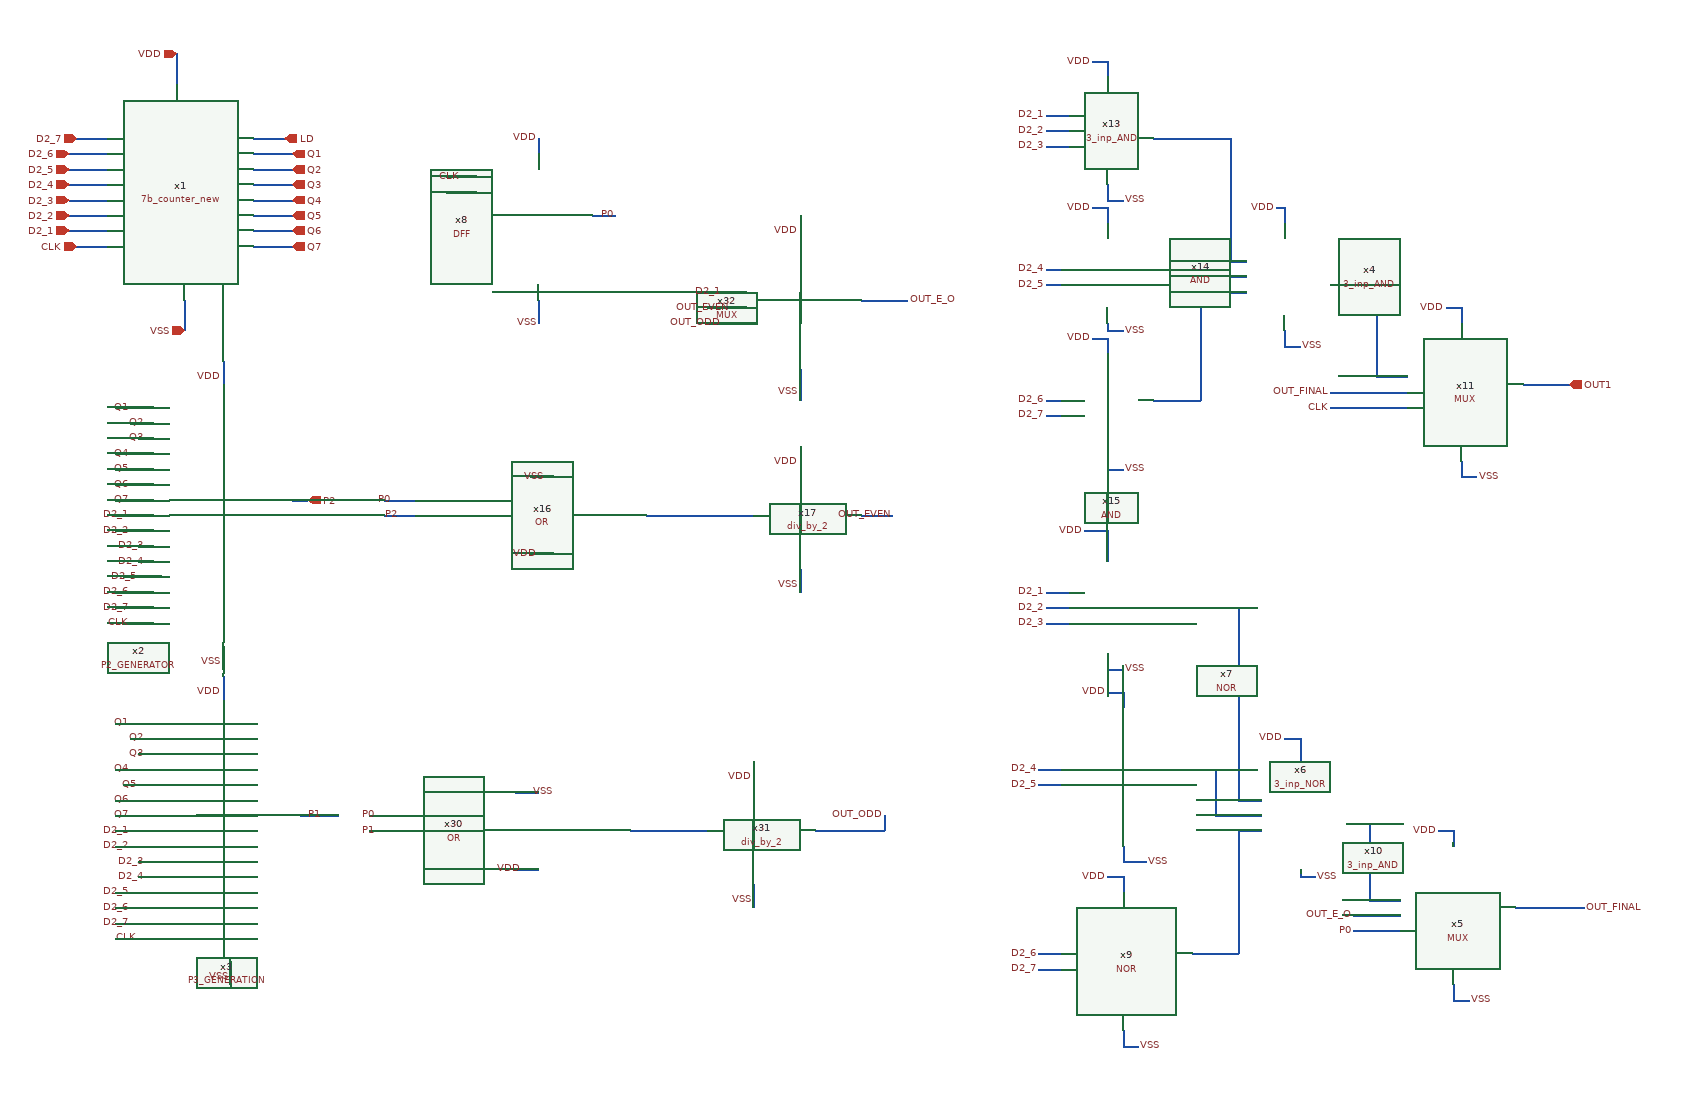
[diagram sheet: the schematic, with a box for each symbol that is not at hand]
v {xschem version=3.4.5 file_version=1.2
}
G {}
K {}
V {}
S {}
E {}
N 1970 -1710 1970 -1670 {
lab=VDD}
N 1980 -1390 1980 -1350 {
lab=VSS}
N 1840 -1460 1880 -1460 {
lab=CLK}
N 2070 -1600 2110 -1600 {
lab=LD}
N 1830 -1480 1880 -1480 {
lab=D2_1}
N 1830 -1520 1880 -1520 {
lab=D2_3}
N 1830 -1500 1880 -1500 {
lab=D2_2}
N 1830 -1540 1880 -1540 {
lab=D2_4}
N 1830 -1560 1880 -1560 {
lab=D2_5}
N 1830 -1580 1880 -1580 {
lab=D2_6}
N 1840 -1600 1880 -1600 {
lab=D2_7}
N 2070 -1580 2120 -1580 {
lab=Q1}
N 2070 -1560 2120 -1560 {
lab=Q2}
N 2070 -1540 2120 -1540 {
lab=Q3}
N 2070 -1520 2120 -1520 {
lab=Q4}
N 2070 -1500 2120 -1500 {
lab=Q5}
N 2070 -1480 2120 -1480 {
lab=Q6}
N 2070 -1460 2120 -1460 {
lab=Q7}
N 1890 -1250 1940 -1250 {
lab=Q1}
N 1890 -1090 1940 -1090 {
lab=D2_2}
N 1910 -1230 1940 -1230 {
lab=Q2}
N 1920 -1070 1940 -1070 {
lab=D2_3}
N 1920 -1210 1940 -1210 {
lab=Q3}
N 1920 -1050 1940 -1050 {
lab=D2_4}
N 1890 -1190 1940 -1190 {
lab=Q4}
N 1900 -1030 1950 -1030 {
lab=D2_5}
N 1890 -1170 1940 -1170 {
lab=Q5}
N 1890 -1010 1940 -1010 {
lab=D2_6}
N 1890 -1150 1940 -1150 {
lab=Q6}
N 1890 -990 1940 -990 {
lab=D2_7}
N 1890 -1130 1940 -1130 {
lab=Q7}
N 1890 -1110 1940 -1110 {
lab=D2_1}
N 2240 -1130 2280 -1130 {
lab=P0}
N 2240 -1110 2280 -1110 {
lab=P2}
N 2430 -1060 2460 -1060 {
lab=VDD}
N 2430 -1160 2460 -1160 {
lab=VSS}
N 2670 -1110 2720 -1110 {
lab=#net1}
N 2780 -1200 2780 -1170 {
lab=VDD}
N 2780 -1040 2780 -1010 {
lab=VSS}
N 2860 -1110 2900 -1110 {
lab=OUT_EVEN}
N 2320 -1550 2360 -1550 {
lab=CLK}
N 2320 -1530 2360 -1530 {
lab=LD}
N 1890 -840 1940 -840 {
lab=Q1}
N 1890 -680 1940 -680 {
lab=D2_2}
N 1910 -820 1940 -820 {
lab=Q2}
N 1920 -660 1940 -660 {
lab=D2_3}
N 1920 -800 1940 -800 {
lab=Q3}
N 1920 -640 1940 -640 {
lab=D2_4}
N 1890 -780 1940 -780 {
lab=Q4}
N 1890 -620 1940 -620 {
lab=D2_5}
N 1900 -760 1950 -760 {
lab=Q5}
N 1890 -600 1940 -600 {
lab=D2_6}
N 1890 -740 1940 -740 {
lab=Q6}
N 1890 -560 1940 -560 {
lab=CLK}
N 1890 -720 1940 -720 {
lab=Q7}
N 1890 -700 1940 -700 {
lab=D2_1}
N 2220 -720 2260 -720 {
lab=P0}
N 2220 -700 2260 -700 {
lab=P1}
N 2410 -650 2440 -650 {
lab=VDD}
N 2720 -630 2720 -600 {
lab=VSS}
N 2800 -700 2850 -700 {
lab=OUT_ODD}
N 2720 -790 2720 -760 {
lab=VDD}
N 2410 -750 2440 -750 {
lab=VSS}
N 2560 -700 2600 -700 {
lab=#net2}
N 2780 -1500 2780 -1460 {
lab=VDD}
N 2780 -1300 2780 -1260 {
lab=VSS}
N 2660 -1400 2710 -1400 {
lab=D2_1}
N 2660 -1380 2710 -1380 {
lab=OUT_EVEN}
N 2660 -1360 2710 -1360 {
lab=OUT_ODD}
N 2860 -1390 2920 -1390 {
lab=OUT_E_O}
N 2600 -700 2660 -700 {
lab=#net2}
N 2580 -1110 2670 -1110 {
lab=#net1}
N 2510 -1500 2540 -1500 {
lab=P0}
N 2440 -1390 2440 -1360 {
lab=VSS}
N 2440 -1600 2440 -1580 {
lab=VDD}
N 1900 -970 1940 -970 {
lab=CLK}
N 2120 -1130 2140 -1130 {
lab=P2}
N 1890 -580 1940 -580 {
lab=D2_7}
N 2130 -720 2180 -720 {
lab=P1}
N 2030 -1310 2030 -1280 {
lab=VDD}
N 2030 -900 2030 -870 {
lab=VDD}
N 2030 -940 2030 -910 {
lab=VSS}
N 2040 -530 2040 -500 {
lab=VSS}
N 2890 -720 2890 -700 {
lab=OUT_ODD}
N 2850 -700 2890 -700 {
lab=OUT_ODD}
N 3180 -1090 3180 -1050 {
lab=VDD}
N 3150 -1090 3180 -1090 {
lab=VDD}
N 3180 -930 3180 -910 {
lab=VSS}
N 3180 -910 3200 -910 {
lab=VSS}
N 3200 -880 3200 -860 {
lab=VDD}
N 3180 -880 3200 -880 {
lab=VDD}
N 3200 -680 3200 -660 {
lab=VSS}
N 3200 -660 3230 -660 {
lab=VSS}
N 3200 -640 3200 -620 {
lab=VDD}
N 3180 -640 3200 -640 {
lab=VDD}
N 3200 -440 3200 -420 {
lab=VSS}
N 3200 -420 3220 -420 {
lab=VSS}
N 3290 -540 3350 -540 {
lab=#net3}
N 3350 -700 3350 -540 {
lab=#net3}
N 3350 -700 3380 -700 {
lab=#net3}
N 3290 -780 3320 -780 {
lab=#net4}
N 3320 -780 3320 -720 {
lab=#net4}
N 3320 -720 3380 -720 {
lab=#net4}
N 3290 -990 3350 -990 {
lab=#net5}
N 3350 -990 3350 -740 {
lab=#net5}
N 3350 -740 3380 -740 {
lab=#net5}
N 3430 -820 3430 -790 {
lab=VDD}
N 3410 -820 3430 -820 {
lab=VDD}
N 3100 -1010 3130 -1010 {
lab=D2_1}
N 3100 -990 3130 -990 {
lab=D2_2}
N 3100 -970 3130 -970 {
lab=D2_3}
N 3090 -780 3120 -780 {
lab=D2_4}
N 3090 -760 3120 -760 {
lab=D2_5}
N 3090 -540 3120 -540 {
lab=D2_6}
N 3090 -520 3120 -520 {
lab=D2_7}
N 3630 -700 3630 -680 {
lab=VDD}
N 3610 -700 3630 -700 {
lab=VDD}
N 3630 -500 3630 -480 {
lab=VSS}
N 3630 -480 3650 -480 {
lab=VSS}
N 3490 -710 3520 -710 {
lab=#net6}
N 3520 -710 3520 -610 {
lab=#net6}
N 3520 -610 3560 -610 {
lab=#net6}
N 3500 -590 3560 -590 {
lab=OUT_E_O}
N 3500 -570 3560 -570 {
lab=P0}
N 3430 -640 3450 -640 {
lab=VSS}
N 3430 -650 3430 -640 {
lab=VSS}
N 3710 -600 3800 -600 {
lab=OUT_FINAL}
N 3180 -1700 3180 -1680 {
lab=VDD}
N 3160 -1700 3180 -1700 {
lab=VDD}
N 3180 -1540 3180 -1520 {
lab=VSS}
N 3180 -1520 3200 -1520 {
lab=VSS}
N 3180 -1510 3180 -1490 {
lab=VDD}
N 3160 -1510 3180 -1510 {
lab=VDD}
N 3180 -1360 3180 -1350 {
lab=VSS}
N 3180 -1350 3200 -1350 {
lab=VSS}
N 3180 -1340 3180 -1320 {
lab=VDD}
N 3160 -1340 3180 -1340 {
lab=VDD}
N 3180 -1190 3180 -1170 {
lab=VSS}
N 3180 -1170 3200 -1170 {
lab=VSS}
N 3240 -1260 3270 -1260 {
lab=#net7}
N 3240 -1430 3270 -1430 {
lab=#net8}
N 3240 -1600 3270 -1600 {
lab=#net9}
N 3100 -1630 3130 -1630 {
lab=D2_1}
N 3100 -1610 3130 -1610 {
lab=D2_2}
N 3100 -1590 3130 -1590 {
lab=D2_3}
N 3100 -1430 3120 -1430 {
lab=D2_4}
N 3100 -1410 3120 -1410 {
lab=D2_5}
N 3100 -1260 3120 -1260 {
lab=D2_6}
N 3100 -1240 3120 -1240 {
lab=D2_7}
N 3270 -1260 3300 -1260 {
lab=#net7}
N 3300 -1400 3300 -1260 {
lab=#net7}
N 3300 -1400 3360 -1400 {
lab=#net7}
N 3270 -1430 3330 -1430 {
lab=#net8}
N 3330 -1430 3330 -1420 {
lab=#net8}
N 3330 -1420 3360 -1420 {
lab=#net8}
N 3270 -1600 3340 -1600 {
lab=#net9}
N 3340 -1600 3340 -1440 {
lab=#net9}
N 3340 -1440 3360 -1440 {
lab=#net9}
N 3410 -1510 3410 -1490 {
lab=VDD}
N 3400 -1510 3410 -1510 {
lab=VDD}
N 3410 -1350 3410 -1330 {
lab=VSS}
N 3410 -1330 3430 -1330 {
lab=VSS}
N 3470 -1410 3500 -1410 {
lab=#net10}
N 3640 -1380 3640 -1360 {
lab=VDD}
N 3620 -1380 3640 -1380 {
lab=VDD}
N 3640 -1180 3640 -1160 {
lab=VSS}
N 3640 -1160 3660 -1160 {
lab=VSS}
N 3500 -1410 3530 -1410 {
lab=#net10}
N 3530 -1410 3530 -1290 {
lab=#net10}
N 3530 -1290 3570 -1290 {
lab=#net10}
N 3470 -1270 3570 -1270 {
lab=OUT_FINAL}
N 3470 -1250 3570 -1250 {
lab=CLK}
N 3720 -1280 3780 -1280 {
lab=OUT1}
C {devices/iopin.sym} 1970 -1710 3 0 {name=p1 lab=VDD}
C {devices/iopin.sym} 1980 -1350 1 0 {name=p2 lab=VSS}
C {devices/ipin.sym} 1830 -1480 0 0 {name=p3 lab=D2_1}
C {devices/ipin.sym} 1840 -1460 0 0 {name=p4 lab=CLK}
C {devices/ipin.sym} 1830 -1500 0 0 {name=p5 lab=D2_2}
C {devices/ipin.sym} 1830 -1520 0 0 {name=p6 lab=D2_3}
C {devices/ipin.sym} 1830 -1540 0 0 {name=p7 lab=D2_4}
C {devices/ipin.sym} 1830 -1560 0 0 {name=p8 lab=D2_5}
C {devices/ipin.sym} 1830 -1580 0 0 {name=p9 lab=D2_6}
C {devices/ipin.sym} 1840 -1600 0 0 {name=p10 lab=D2_7}
C {devices/opin.sym} 2110 -1600 0 0 {name=p12 lab=LD}
C {devices/opin.sym} 2120 -1580 0 0 {name=p13 lab=Q1}
C {devices/opin.sym} 2120 -1560 0 0 {name=p14 lab=Q2}
C {devices/opin.sym} 2120 -1540 0 0 {name=p15 lab=Q3}
C {devices/opin.sym} 2120 -1520 0 0 {name=p16 lab=Q4}
C {devices/opin.sym} 2120 -1500 0 0 {name=p17 lab=Q5}
C {devices/opin.sym} 2120 -1480 0 0 {name=p18 lab=Q6}
C {devices/opin.sym} 2120 -1460 0 0 {name=p19 lab=Q7}
C {devices/lab_wire.sym} 1910 -1250 0 0 {name=p27 sig_type=std_logic lab=Q1}
C {devices/lab_wire.sym} 1930 -1230 0 0 {name=p28 sig_type=std_logic lab=Q2}
C {devices/lab_wire.sym} 1930 -1210 0 0 {name=p29 sig_type=std_logic lab=Q3}
C {devices/lab_wire.sym} 1930 -1050 0 0 {name=p30 sig_type=std_logic lab=D2_4}
C {devices/lab_wire.sym} 1930 -1070 0 0 {name=p31 sig_type=std_logic lab=D2_3}
C {devices/lab_wire.sym} 1910 -1090 0 0 {name=p32 sig_type=std_logic lab=D2_2}
C {devices/opin.sym} 2140 -1130 0 0 {name=p43 lab=P2}
C {devices/lab_wire.sym} 1910 -1190 0 0 {name=p47 sig_type=std_logic lab=Q4}
C {devices/lab_wire.sym} 1920 -1030 0 0 {name=p48 sig_type=std_logic lab=D2_5}
C {devices/lab_wire.sym} 1910 -1170 0 0 {name=p52 sig_type=std_logic lab=Q5}
C {devices/lab_wire.sym} 1910 -1010 0 0 {name=p53 sig_type=std_logic lab=D2_6}
C {devices/lab_wire.sym} 1910 -1150 0 0 {name=p57 sig_type=std_logic lab=Q6}
C {devices/lab_wire.sym} 1910 -990 0 0 {name=p58 sig_type=std_logic lab=D2_7}
C {devices/lab_wire.sym} 1910 -1130 0 0 {name=p62 sig_type=std_logic lab=Q7}
C {OR.sym} 2430 -1110 0 0 {name=x16}
C {devices/lab_wire.sym} 2440 -1060 1 0 {name=p84 sig_type=std_logic lab=VDD}
C {devices/lab_wire.sym} 2450 -1160 3 0 {name=p85 sig_type=std_logic lab=VSS}
C {div_by_2.sym} 2870 -1090 0 0 {name=x17}
C {devices/lab_wire.sym} 2780 -1180 0 0 {name=p86 sig_type=std_logic lab=VDD}
C {devices/lab_wire.sym} 2780 -1020 0 0 {name=p87 sig_type=std_logic lab=VSS}
C {7b_counter_new.sym} 2030 -1510 0 0 {name=x1}
C {devices/lab_wire.sym} 1910 -1110 0 0 {name=p11 sig_type=std_logic lab=D2_1}
C {devices/lab_wire.sym} 2340 -1530 0 0 {name=p20 sig_type=std_logic lab=LD}
C {DFF.sym} 2510 -1530 0 0 {name=x8}
C {devices/lab_wire.sym} 2440 -1600 0 0 {name=p40 sig_type=std_logic lab=VDD}
C {devices/lab_wire.sym} 2440 -1360 0 0 {name=p41 sig_type=std_logic lab=VSS}
C {devices/lab_wire.sym} 2340 -1550 0 0 {name=p42 sig_type=std_logic lab=CLK}
C {devices/lab_wire.sym} 2250 -1130 0 0 {name=p63 sig_type=std_logic lab=P0}
C {devices/lab_wire.sym} 1910 -840 0 0 {name=p82 sig_type=std_logic lab=Q1}
C {devices/lab_wire.sym} 1930 -820 0 0 {name=p89 sig_type=std_logic lab=Q2}
C {devices/lab_wire.sym} 1930 -800 0 0 {name=p90 sig_type=std_logic lab=Q3}
C {devices/lab_wire.sym} 1930 -640 0 0 {name=p91 sig_type=std_logic lab=D2_4}
C {devices/lab_wire.sym} 1930 -660 0 0 {name=p92 sig_type=std_logic lab=D2_3}
C {devices/lab_wire.sym} 1910 -680 0 0 {name=p93 sig_type=std_logic lab=D2_2}
C {devices/lab_wire.sym} 1910 -780 0 0 {name=p101 sig_type=std_logic lab=Q4}
C {devices/lab_wire.sym} 1910 -620 0 0 {name=p102 sig_type=std_logic lab=D2_5}
C {devices/lab_wire.sym} 1920 -760 0 0 {name=p106 sig_type=std_logic lab=Q5}
C {devices/lab_wire.sym} 1910 -600 0 0 {name=p107 sig_type=std_logic lab=D2_6}
C {devices/lab_wire.sym} 1910 -740 0 0 {name=p111 sig_type=std_logic lab=Q6}
C {devices/lab_wire.sym} 1920 -560 0 0 {name=p112 sig_type=std_logic lab=CLK}
C {devices/lab_wire.sym} 1910 -720 0 0 {name=p116 sig_type=std_logic lab=Q7}
C {devices/lab_wire.sym} 1910 -700 0 0 {name=p118 sig_type=std_logic lab=D2_1}
C {OR.sym} 2410 -700 0 0 {name=x30}
C {devices/lab_wire.sym} 2230 -700 0 0 {name=p88 sig_type=std_logic lab=P1}
C {devices/lab_wire.sym} 2420 -650 1 0 {name=p126 sig_type=std_logic lab=VDD}
C {devices/lab_wire.sym} 2720 -610 0 0 {name=p143 sig_type=std_logic lab=VSS}
C {div_by_2.sym} 2810 -680 0 0 {name=x31}
C {devices/lab_wire.sym} 2720 -770 0 0 {name=p144 sig_type=std_logic lab=VDD}
C {devices/lab_wire.sym} 2430 -750 2 0 {name=p145 sig_type=std_logic lab=VSS}
C {devices/lab_wire.sym} 2230 -720 0 0 {name=p146 sig_type=std_logic lab=P0}
C {devices/lab_wire.sym} 2890 -720 0 0 {name=p147 sig_type=std_logic lab=OUT_ODD}
C {devices/opin.sym} 3780 -1280 0 0 {name=p69 lab=OUT1}
C {MUX.sym} 2860 -1380 0 0 {name=x32}
C {devices/lab_wire.sym} 2680 -1400 0 0 {name=p149 sig_type=std_logic lab=D2_1}
C {devices/lab_wire.sym} 2900 -1110 0 0 {name=p150 sig_type=std_logic lab=OUT_EVEN}
C {devices/lab_wire.sym} 2690 -1380 0 0 {name=p151 sig_type=std_logic lab=OUT_EVEN}
C {devices/lab_wire.sym} 2680 -1360 0 0 {name=p152 sig_type=std_logic lab=OUT_ODD}
C {devices/lab_wire.sym} 2780 -1480 0 0 {name=p153 sig_type=std_logic lab=VDD}
C {devices/lab_wire.sym} 2780 -1270 0 0 {name=p154 sig_type=std_logic lab=VSS}
C {devices/lab_wire.sym} 2540 -1500 0 0 {name=p165 sig_type=std_logic lab=P0}
C {devices/lab_wire.sym} 2260 -1110 0 0 {name=p44 sig_type=std_logic lab=P2}
C {P2_GENERATOR.sym} 2090 -1110 0 0 {name=x2}
C {devices/lab_wire.sym} 1910 -970 0 0 {name=p21 sig_type=std_logic lab=CLK}
C {P3_GENERATION.sym} 1960 -660 0 0 {name=x3}
C {devices/lab_wire.sym} 1910 -580 0 0 {name=p22 sig_type=std_logic lab=D2_7}
C {devices/lab_wire.sym} 2160 -720 0 0 {name=p23 sig_type=std_logic lab=P1}
C {devices/lab_wire.sym} 2030 -1290 0 0 {name=p24 sig_type=std_logic lab=VDD}
C {devices/lab_wire.sym} 2030 -880 0 0 {name=p25 sig_type=std_logic lab=VDD}
C {devices/lab_wire.sym} 2030 -920 0 0 {name=p26 sig_type=std_logic lab=VSS}
C {devices/lab_wire.sym} 2040 -510 0 0 {name=p33 sig_type=std_logic lab=VSS}
C {MUX.sym} 3710 -590 0 0 {name=x5}
C {3_inp_NOR.sym} 3500 -890 0 0 {name=x6}
C {NOR.sym} 3270 -760 0 0 {name=x7}
C {NOR.sym} 3270 -520 0 0 {name=x9}
C {3_inp_AND.sym} 3530 -720 0 0 {name=x10}
C {devices/lab_wire.sym} 3100 -1010 0 0 {name=p34 sig_type=std_logic lab=D2_1}
C {devices/lab_wire.sym} 3100 -990 0 0 {name=p35 sig_type=std_logic lab=D2_2}
C {devices/lab_wire.sym} 3100 -970 0 0 {name=p36 sig_type=std_logic lab=D2_3}
C {devices/lab_wire.sym} 3090 -780 0 0 {name=p37 sig_type=std_logic lab=D2_4}
C {devices/lab_wire.sym} 3090 -760 0 0 {name=p38 sig_type=std_logic lab=D2_5}
C {devices/lab_wire.sym} 3090 -540 0 0 {name=p39 sig_type=std_logic lab=D2_6}
C {devices/lab_wire.sym} 3090 -520 0 0 {name=p45 sig_type=std_logic lab=D2_7}
C {devices/lab_wire.sym} 3150 -1090 0 0 {name=p46 sig_type=std_logic lab=VDD}
C {devices/lab_wire.sym} 3200 -910 2 0 {name=p49 sig_type=std_logic lab=VSS}
C {devices/lab_wire.sym} 3230 -660 2 0 {name=p50 sig_type=std_logic lab=VSS}
C {devices/lab_wire.sym} 3220 -420 2 0 {name=p51 sig_type=std_logic lab=VSS}
C {devices/lab_wire.sym} 3450 -640 2 0 {name=p54 sig_type=std_logic lab=VSS}
C {devices/lab_wire.sym} 3180 -880 0 0 {name=p55 sig_type=std_logic lab=VDD}
C {devices/lab_wire.sym} 3180 -640 0 0 {name=p56 sig_type=std_logic lab=VDD}
C {devices/lab_wire.sym} 3410 -820 0 0 {name=p59 sig_type=std_logic lab=VDD}
C {devices/lab_wire.sym} 3610 -700 0 0 {name=p61 sig_type=std_logic lab=VDD}
C {devices/lab_wire.sym} 3650 -480 2 0 {name=p65 sig_type=std_logic lab=VSS}
C {devices/lab_wire.sym} 3500 -590 0 0 {name=p66 sig_type=std_logic lab=OUT_E_O}
C {devices/lab_wire.sym} 3500 -570 0 0 {name=p67 sig_type=std_logic lab=P0}
C {devices/lab_wire.sym} 2920 -1390 2 0 {name=p68 sig_type=std_logic lab=OUT_E_O}
C {3_inp_AND.sym} 3280 -1610 0 0 {name=x13}
C {AND.sym} 3270 -1410 0 0 {name=x14}
C {AND.sym} 3270 -1240 0 0 {name=x15}
C {devices/lab_wire.sym} 3160 -1700 0 0 {name=p60 sig_type=std_logic lab=VDD}
C {devices/lab_wire.sym} 3160 -1510 0 0 {name=p64 sig_type=std_logic lab=VDD}
C {devices/lab_wire.sym} 3160 -1340 0 0 {name=p70 sig_type=std_logic lab=VDD}
C {devices/lab_wire.sym} 3200 -1170 2 0 {name=p71 sig_type=std_logic lab=VSS}
C {devices/lab_wire.sym} 3200 -1350 2 0 {name=p72 sig_type=std_logic lab=VSS}
C {devices/lab_wire.sym} 3200 -1520 2 0 {name=p73 sig_type=std_logic lab=VSS}
C {3_inp_AND.sym} 3510 -1420 0 0 {name=x4}
C {devices/lab_wire.sym} 3400 -1510 0 0 {name=p74 sig_type=std_logic lab=VDD}
C {devices/lab_wire.sym} 3430 -1330 2 0 {name=p75 sig_type=std_logic lab=VSS}
C {devices/lab_wire.sym} 3100 -1630 0 0 {name=p76 sig_type=std_logic lab=D2_1}
C {devices/lab_wire.sym} 3100 -1610 0 0 {name=p77 sig_type=std_logic lab=D2_2}
C {devices/lab_wire.sym} 3100 -1590 0 0 {name=p78 sig_type=std_logic lab=D2_3}
C {devices/lab_wire.sym} 3100 -1430 0 0 {name=p79 sig_type=std_logic lab=D2_4}
C {devices/lab_wire.sym} 3100 -1410 0 0 {name=p80 sig_type=std_logic lab=D2_5}
C {devices/lab_wire.sym} 3100 -1260 0 0 {name=p81 sig_type=std_logic lab=D2_6}
C {devices/lab_wire.sym} 3100 -1240 0 0 {name=p83 sig_type=std_logic lab=D2_7}
C {MUX.sym} 3720 -1270 0 0 {name=x11}
C {devices/lab_wire.sym} 3620 -1380 0 0 {name=p94 sig_type=std_logic lab=VDD}
C {devices/lab_wire.sym} 3660 -1160 2 0 {name=p95 sig_type=std_logic lab=VSS}
C {devices/lab_wire.sym} 3800 -600 2 0 {name=p96 sig_type=std_logic lab=OUT_FINAL}
C {devices/lab_wire.sym} 3470 -1270 0 0 {name=p97 sig_type=std_logic lab=OUT_FINAL}
C {devices/lab_wire.sym} 3470 -1250 0 0 {name=p98 sig_type=std_logic lab=CLK}
